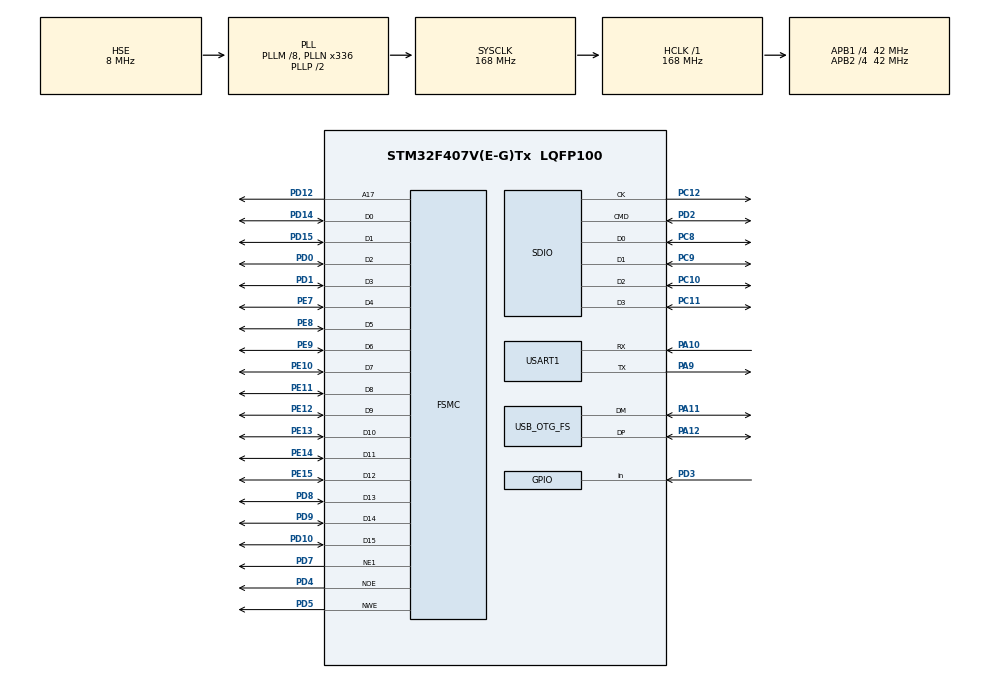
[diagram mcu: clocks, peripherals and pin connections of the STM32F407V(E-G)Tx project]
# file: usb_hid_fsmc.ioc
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FATFS.BSP.number=1
FATFS0.BSP.STBoard=false
FATFS0.BSP.api=Unknown
FATFS0.BSP.i2caddr=0
FATFS0.BSP.instance=PD3
FATFS0.BSP.ip=GPIO
FATFS0.BSP.mode=Input
FATFS0.BSP.name=Detect_SDIO
FATFS0.BSP.solution=PD3
Mcu.Family=STM32F4
Mcu.Name=STM32F407V(E-G)Tx
Mcu.Package=LQFP100
NVIC.OTG_FS_IRQn=true\:0\:0\:false\:false\:true\:false\:true
NVIC.PriorityGroup=NVIC_PRIORITYGROUP_4
NVIC.SDIO_IRQn=true\:0\:0\:false\:false\:true\:true\:true
NVIC.TIM1_UP_TIM10_IRQn=true\:0\:0\:false\:false\:true\:false\:true
NVIC.TimeBase=TIM1_UP_TIM10_IRQn
NVIC.TimeBaseIP=TIM1
NVIC.USART1_IRQn=true\:0\:0\:false\:false\:true\:true\:true
PA10.Mode=Asynchronous
PA10.Signal=USART1_RX
PA11.Mode=Device_Only
PA11.Signal=USB_OTG_FS_DM
PA12.Mode=Device_Only
PA12.Signal=USB_OTG_FS_DP
PA13.Mode=Serial_Wire
PA13.Signal=SYS_JTMS-SWDIO
PA14.Mode=Serial_Wire
PA14.Signal=SYS_JTCK-SWCLK
PA9.Mode=Asynchronous
PA9.Signal=USART1_TX
PC10.Mode=SD_4_bits_Wide_bus
PC10.Signal=SDIO_D2
PC11.Mode=SD_4_bits_Wide_bus
PC11.Signal=SDIO_D3
PC12.Mode=SD_4_bits_Wide_bus
PC12.Signal=SDIO_CK
PC8.Mode=SD_4_bits_Wide_bus
PC8.Signal=SDIO_D0
PC9.Mode=SD_4_bits_Wide_bus
PC9.Signal=SDIO_D1
PD0.Mode=16b-d1
PD0.Signal=FSMC_D2
PD1.Mode=16b-d1
PD1.Signal=FSMC_D3
PD10.Mode=16b-d1
PD10.Signal=FSMC_D15
PD12.Mode=A17_1
PD12.Signal=FSMC_A17
PD14.Mode=16b-d1
PD14.Signal=FSMC_D0
PD15.Mode=16b-d1
PD15.Signal=FSMC_D1
PD2.Mode=SD_4_bits_Wide_bus
PD2.Signal=SDIO_CMD
PD3.Signal=GPIO_Input
PD4.Mode=Lcd1
PD4.Signal=FSMC_NOE
PD5.Mode=Lcd1
PD5.Signal=FSMC_NWE
PD7.Mode=NorPsramChipSelect1_1
PD7.Signal=FSMC_NE1
PD8.Mode=16b-d1
PD8.Signal=FSMC_D13
PD9.Mode=16b-d1
PD9.Signal=FSMC_D14
PE10.Mode=16b-d1
PE10.Signal=FSMC_D7
PE11.Mode=16b-d1
PE11.Signal=FSMC_D8
PE12.Mode=16b-d1
PE12.Signal=FSMC_D9
PE13.Mode=16b-d1
PE13.Signal=FSMC_D10
PE14.Mode=16b-d1
PE14.Signal=FSMC_D11
PE15.Mode=16b-d1
PE15.Signal=FSMC_D12
PE7.Mode=16b-d1
PE7.Signal=FSMC_D4
PE8.Mode=16b-d1
PE8.Signal=FSMC_D5
PE9.Mode=16b-d1
PE9.Signal=FSMC_D6
PH0-OSC_IN.Mode=HSE-External-Oscillator
PH0-OSC_IN.Signal=RCC_OSC_IN
PH1-OSC_OUT.Mode=HSE-External-Oscillator
PH1-OSC_OUT.Signal=RCC_OSC_OUT
ProjectManager.HeapSize=0x200
ProjectManager.StackSize=0x400
ProjectManager.TargetToolchain=Makefile
RCC.48MHZClocksFreq_Value=48000000
RCC.AHBFreq_Value=168000000
RCC.APB1CLKDivider=RCC_HCLK_DIV4
RCC.APB1Freq_Value=42000000
RCC.APB1TimFreq_Value=84000000
RCC.APB2CLKDivider=RCC_HCLK_DIV4
RCC.APB2Freq_Value=42000000
RCC.APB2TimFreq_Value=84000000
RCC.CortexFreq_Value=168000000
RCC.HCLKFreq_Value=168000000
RCC.HSE_VALUE=8000000
RCC.HSI_VALUE=16000000
RCC.LSE_VALUE=32768
RCC.PLLM=4
RCC.PLLN=168
RCC.PLLQ=7
RCC.SYSCLKFreq_VALUE=168000000
RCC.SYSCLKSource=RCC_SYSCLKSOURCE_PLLCLK
RCC.VCOOutputFreq_Value=336000000
USART1.VirtualMode=VM_ASYNC
USB_DEVICE.CLASS_NAME_FS=HID
USB_DEVICE.VirtualMode-HID_FS=Hid
USB_DEVICE.VirtualModeFS=Hid_FS
USB_OTG_FS.VirtualMode=Device_Only
VP_FATFS_VS_SDIO.Mode=SDIO
VP_SYS_VS_tim1.Mode=TIM1
VP_TIM6_VS_ClockSourceINT.Mode=Enable_Timer
VP_USB_DEVICE_VS_USB_DEVICE_HID_FS.Mode=HID_FS
board=custom

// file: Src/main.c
/* USER CODE BEGIN Header */
/**
  ******************************************************************************
  * @file           : main.c
  * @brief          : Main program body
  ******************************************************************************
  * @attention
  *
  * <h2><center>&copy; Copyright (c) 2020 STMicroelectronics.
  * All rights reserved.</center></h2>
  *
  * This software component is licensed by ST under Ultimate Liberty license
  * SLA0044, the "License"; You may not use this file except in compliance with
  * the License. You may obtain a copy of the License at:
  *                             www.st.com/SLA0044
  *
  ******************************************************************************
  */
/* USER CODE END Header */

#include "main.h"
#include "fatfs.h"
//#include "usb_device.h"
#include "ILI9488.h"
#include "bootloader.h"
#include "board.h"

SD_HandleTypeDef hsd;
TIM_HandleTypeDef htim6;
UART_HandleTypeDef huart1;
SRAM_HandleTypeDef hsram1;
DMA_HandleTypeDef hdma_spi1_rx;
DMA_HandleTypeDef hdma_spi1_tx;
/* USER CODE BEGIN PV */
SPI_HandleTypeDef hspi1;

/* USER CODE END PV */

void SystemClock_Config(void);
static void MX_GPIO_Init(void);
static void MX_FSMC_Init(void);
static void MX_TIM6_Init(void);
static void MX_SDIO_SD_Init(void);
static void MX_USART1_UART_Init(void);
//static void MX_SPI1_Init(void);
static void MX_DMA_Init(void);

char txt[60];
int main(void)
{

  HAL_Init();

  SystemClock_Config();

  MX_GPIO_Init();
  MX_FSMC_Init();
  MX_TIM6_Init();
  MX_DMA_Init();
  #if 0
  MX_USB_DEVICE_Init();
  #else
  #endif
  MX_SDIO_SD_Init();
  MX_USART1_UART_Init();
  MX_FATFS_Init();
  TFT_Switch_Init();
  TFT_Clear(Black);

  printf("\r\nBooting....Usart\r\n");
  TFT_DrawString(0,0,"Booting..LCD" ,Green);

  bootloader_start();
  while (1)
  {
   printf("main while loop, should not be here ");
  }
  /* USER CODE END 3 */
}

void SystemClock_Config(void)
{
  RCC_OscInitTypeDef RCC_OscInitStruct = {0};
  RCC_ClkInitTypeDef RCC_ClkInitStruct = {0};

  /** Configure the main internal regulator output voltage
  */
  __HAL_RCC_PWR_CLK_ENABLE();
  __HAL_PWR_VOLTAGESCALING_CONFIG(PWR_REGULATOR_VOLTAGE_SCALE1);
  /** Initializes the CPU, AHB and APB busses clocks
  */
  RCC_OscInitStruct.OscillatorType = RCC_OSCILLATORTYPE_HSE;
  RCC_OscInitStruct.HSEState = RCC_HSE_ON;
  RCC_OscInitStruct.PLL.PLLState = RCC_PLL_ON;
  RCC_OscInitStruct.PLL.PLLSource = RCC_PLLSOURCE_HSE;
  RCC_OscInitStruct.PLL.PLLM = 8;
  RCC_OscInitStruct.PLL.PLLN = 336;
  RCC_OscInitStruct.PLL.PLLP = RCC_PLLP_DIV2;
  RCC_OscInitStruct.PLL.PLLQ = 7;
  if (HAL_RCC_OscConfig(&RCC_OscInitStruct) != HAL_OK)
  {
    Error_Handler();
  }
  /** Initializes the CPU, AHB and APB busses clocks
  */
  RCC_ClkInitStruct.ClockType = RCC_CLOCKTYPE_HCLK|RCC_CLOCKTYPE_SYSCLK
                              |RCC_CLOCKTYPE_PCLK1|RCC_CLOCKTYPE_PCLK2;
  RCC_ClkInitStruct.SYSCLKSource = RCC_SYSCLKSOURCE_PLLCLK;
  RCC_ClkInitStruct.AHBCLKDivider = RCC_SYSCLK_DIV1;
  RCC_ClkInitStruct.APB1CLKDivider = RCC_HCLK_DIV4;
  RCC_ClkInitStruct.APB2CLKDivider = RCC_HCLK_DIV4;

  if (HAL_RCC_ClockConfig(&RCC_ClkInitStruct, FLASH_LATENCY_5) != HAL_OK)
  {
    Error_Handler();
  }
}

static void MX_SDIO_SD_Init(void)
{

  hsd.Instance = SDIO;
  hsd.Init.ClockEdge = SDIO_CLOCK_EDGE_RISING;
  hsd.Init.ClockBypass = SDIO_CLOCK_BYPASS_DISABLE;
  hsd.Init.ClockPowerSave = SDIO_CLOCK_POWER_SAVE_DISABLE;
  hsd.Init.BusWide = SDIO_BUS_WIDE_1B;
  hsd.Init.HardwareFlowControl = SDIO_HARDWARE_FLOW_CONTROL_DISABLE;
  hsd.Init.ClockDiv = 0;

}

static void MX_TIM6_Init(void)
{

  TIM_MasterConfigTypeDef sMasterConfig = {0};

  htim6.Instance = TIM6;
  htim6.Init.Prescaler = 1000;
  htim6.Init.CounterMode = TIM_COUNTERMODE_UP;
  htim6.Init.Period = 999;
  //htim6.Init.AutoReloadPreload = TIM_AUTORELOAD_PRELOAD_DISABLE;
  if (HAL_TIM_Base_Init(&htim6) != HAL_OK)
  {
    Error_Handler();
  }
  sMasterConfig.MasterOutputTrigger = TIM_TRGO_RESET;
  sMasterConfig.MasterSlaveMode = TIM_MASTERSLAVEMODE_DISABLE;
  if (HAL_TIMEx_MasterConfigSynchronization(&htim6, &sMasterConfig) != HAL_OK)
  {
    Error_Handler();
  }

}
/*
Dma Config

*/static void MX_DMA_Init(void)
{
  /* DMA controller clock enable */
  __HAL_RCC_DMA2_CLK_ENABLE();

  /* DMA interrupt init */
  /* DMA2_Stream0_IRQn interrupt configuration */
  HAL_NVIC_SetPriority(DMA2_Stream0_IRQn, 0, 0);
  HAL_NVIC_EnableIRQ(DMA2_Stream0_IRQn);
  /* DMA2_Stream3_IRQn interrupt configuration */
  HAL_NVIC_SetPriority(DMA2_Stream3_IRQn, 0, 0);
  HAL_NVIC_EnableIRQ(DMA2_Stream3_IRQn);
  /* DMA2_Stream5_IRQn interrupt configuration */
  HAL_NVIC_SetPriority(DMA2_Stream5_IRQn, 0, 0);
  HAL_NVIC_EnableIRQ(DMA2_Stream5_IRQn);
  /* DMA2_Stream6_IRQn interrupt configuration */
  HAL_NVIC_SetPriority(DMA2_Stream6_IRQn, 0, 0);
  HAL_NVIC_EnableIRQ(DMA2_Stream6_IRQn);

}

static void MX_USART1_UART_Init(void)
{

  huart1.Instance = USART1;
  huart1.Init.BaudRate = 115200;
  huart1.Init.WordLength = UART_WORDLENGTH_8B;
  huart1.Init.StopBits = UART_STOPBITS_1;
  huart1.Init.Parity = UART_PARITY_NONE;
  huart1.Init.Mode = UART_MODE_TX_RX;
  huart1.Init.HwFlowCtl = UART_HWCONTROL_NONE;
  huart1.Init.OverSampling = UART_OVERSAMPLING_16;
  if (HAL_UART_Init(&huart1) != HAL_OK)
  {
    Error_Handler();
  }

}

static void MX_GPIO_Init(void)
{
  GPIO_InitTypeDef GPIO_InitStruct = {0};

  /* GPIO Ports Clock Enable */
  __HAL_RCC_GPIOH_CLK_ENABLE();
  __HAL_RCC_GPIOE_CLK_ENABLE();
  __HAL_RCC_GPIOB_CLK_ENABLE();
  __HAL_RCC_GPIOD_CLK_ENABLE();
  __HAL_RCC_GPIOC_CLK_ENABLE();
  __HAL_RCC_GPIOA_CLK_ENABLE();

  /*Configure GPIO pin : PD3 */
  GPIO_InitStruct.Pin = GPIO_PIN_3;
  GPIO_InitStruct.Mode = GPIO_MODE_INPUT;
  GPIO_InitStruct.Pull = GPIO_NOPULL;
  HAL_GPIO_Init(GPIOD, &GPIO_InitStruct);

  GPIO_InitStruct.Pin = GPIO_PIN_1;
  GPIO_InitStruct.Mode = GPIO_MODE_OUTPUT_PP;
  GPIO_InitStruct.Pull = GPIO_NOPULL;
  HAL_GPIO_Init(GPIOA, &GPIO_InitStruct);
  HAL_GPIO_WritePin(GPIOA,GPIO_PIN_1,GPIO_PIN_SET);

 GPIO_InitStruct.Pin = GPIO_PIN_4;
  GPIO_InitStruct.Mode = GPIO_MODE_OUTPUT_PP;
  GPIO_InitStruct.Pull = GPIO_PULLUP;
  HAL_GPIO_Init(GPIOC, &GPIO_InitStruct);

GPIO_InitStruct.Pin = GPIO_PIN_0;
  GPIO_InitStruct.Mode = GPIO_MODE_OUTPUT_PP;
  GPIO_InitStruct.Pull = GPIO_NOPULL;
  HAL_GPIO_Init(GPIOB, &GPIO_InitStruct);
   HAL_GPIO_WritePin(GPIOB,GPIO_PIN_0,GPIO_PIN_RESET);
}

/* FSMC initialization function */
static void MX_FSMC_Init(void)
{

  FSMC_NORSRAM_TimingTypeDef Timing = {0};

  hsram1.Instance = FSMC_NORSRAM_DEVICE;
  hsram1.Extended = FSMC_NORSRAM_EXTENDED_DEVICE;
  /* hsram1.Init */
  hsram1.Init.NSBank = FSMC_NORSRAM_BANK1;
  hsram1.Init.DataAddressMux = FSMC_DATA_ADDRESS_MUX_DISABLE;
  hsram1.Init.MemoryType = FSMC_MEMORY_TYPE_SRAM;
  hsram1.Init.MemoryDataWidth = FSMC_NORSRAM_MEM_BUS_WIDTH_16;
  hsram1.Init.BurstAccessMode = FSMC_BURST_ACCESS_MODE_DISABLE;
  hsram1.Init.WaitSignalPolarity = FSMC_WAIT_SIGNAL_POLARITY_LOW;
  hsram1.Init.WrapMode = FSMC_WRAP_MODE_DISABLE;
  hsram1.Init.WaitSignalActive = FSMC_WAIT_TIMING_BEFORE_WS;
  hsram1.Init.WriteOperation = FSMC_WRITE_OPERATION_ENABLE;
  hsram1.Init.WaitSignal = FSMC_WAIT_SIGNAL_DISABLE;
  hsram1.Init.ExtendedMode = FSMC_EXTENDED_MODE_DISABLE;
  hsram1.Init.AsynchronousWait = FSMC_ASYNCHRONOUS_WAIT_DISABLE;
  hsram1.Init.WriteBurst = FSMC_WRITE_BURST_DISABLE;
  hsram1.Init.PageSize = FSMC_PAGE_SIZE_NONE;
  /* Timing */
  Timing.AddressSetupTime = 5;
  Timing.AddressHoldTime = 0;
  Timing.DataSetupTime = 2;
  Timing.BusTurnAroundDuration = 0;
  Timing.CLKDivision = 1;
  Timing.DataLatency = 1;
  Timing.AccessMode = FSMC_ACCESS_MODE_A;
  /* ExtTiming */

  if (HAL_SRAM_Init(&hsram1, &Timing, NULL) != HAL_OK)
  {
    Error_Handler( );
  }

}

void HAL_TIM_PeriodElapsedCallback(TIM_HandleTypeDef *htim)
{
  if (htim->Instance == TIM1) {
    HAL_IncTick();
  }
}

void Error_Handler(void)
{
}

/************************ (C) COPYRIGHT STMicroelectronics *****END OF FILE****/
